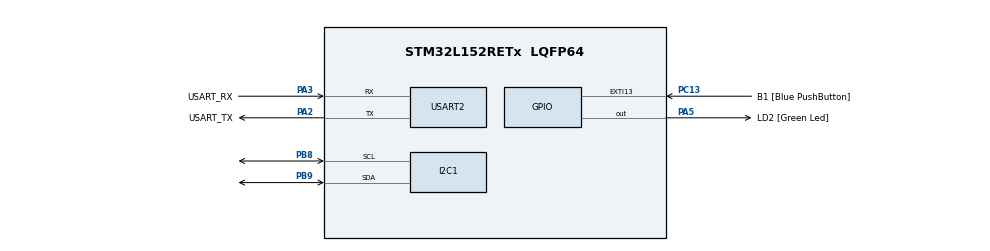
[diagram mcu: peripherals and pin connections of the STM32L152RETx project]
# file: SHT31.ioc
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Mcu.Family=STM32L1
Mcu.Name=STM32L152RETx
Mcu.Package=LQFP64
NVIC.PriorityGroup=NVIC_PRIORITYGROUP_0
PA13.GPIO_Label=TMS
PA13.Mode=Serial_Wire
PA13.Signal=SYS_JTMS-SWDIO
PA14.GPIO_Label=TCK
PA14.Mode=Serial_Wire
PA14.Signal=SYS_JTCK-SWCLK
PA2.GPIO_Label=USART_TX
PA2.Mode=Asynchronous
PA2.Signal=USART2_TX
PA3.GPIO_Label=USART_RX
PA3.Mode=Asynchronous
PA3.Signal=USART2_RX
PA5.GPIO_Label=LD2 [Green Led]
PA5.Signal=GPIO_Output
PB3.GPIO_Label=SWO
PB3.Signal=SYS_JTDO-TRACESWO
PB8.Mode=I2C
PB8.Signal=I2C1_SCL
PB9.Mode=I2C
PB9.Signal=I2C1_SDA
PC13-WKUP2.GPIO_Label=B1 [Blue PushButton]
PC13-WKUP2.Signal=GPXTI13
PC14-OSC32_IN.Mode=LSE-External-Oscillator
PC14-OSC32_IN.Signal=RCC_OSC32_IN
PC15-OSC32_OUT.Mode=LSE-External-Oscillator
PC15-OSC32_OUT.Signal=RCC_OSC32_OUT
PH0-OSC_IN.Mode=HSE-External-Clock-Source
PH0-OSC_IN.Signal=RCC_OSC_IN
PH1-OSC_OUT.Signal=RCC_OSC_OUT
ProjectManager.HeapSize=0x200
ProjectManager.StackSize=0x400
ProjectManager.TargetToolchain=STM32CubeIDE
RCC.48MHZClocksFreq_Value=48000000
RCC.AHBFreq_Value=32000000
RCC.APB1Freq_Value=32000000
RCC.APB1TimFreq_Value=32000000
RCC.APB2Freq_Value=32000000
RCC.APB2TimFreq_Value=32000000
RCC.HCLKFreq_Value=32000000
RCC.HSE_VALUE=8000000
RCC.HSI_VALUE=16000000
RCC.MSI_VALUE=2097000
RCC.PLLDIV=RCC_PLL_DIV3
RCC.PLLMUL=RCC_PLL_MUL6
RCC.RTCClockSelectionVirtual=RCC_RTCCLKSOURCE_LSE
RCC.SYSCLKFreq_VALUE=32000000
RCC.SYSCLKSource=RCC_SYSCLKSOURCE_PLLCLK
RCC.USBOutput=48000000
RCC.VCOOutputFreq_Value=96000000
USART2.VirtualMode=VM_ASYNC
board=NUCLEO-L152RE

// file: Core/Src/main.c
/* USER CODE BEGIN Header */
/**
  ******************************************************************************
  * @file           : main.c
  * @brief          : Main program body
  ******************************************************************************
  * @attention
  *
  * Copyright (c) 2024 STMicroelectronics.
  * All rights reserved.
  *
  * This software is licensed under terms that can be found in the LICENSE file
  * in the root directory of this software component.
  * If no LICENSE file comes with this software, it is provided AS-IS.
  *
  ******************************************************************************
  */
/* USER CODE END Header */
#include "main.h"
#include "i2c.h"
#include "usart.h"
#include "gpio.h"

/* USER CODE BEGIN Includes */
#include "MY_DHT22.h"
/* USER CODE END Includes */

/* USER CODE BEGIN PV */
/* Private variables ---------------------------------------------------------*/

/* USER CODE END PV */

void SystemClock_Config(void);
/* USER CODE BEGIN PFP */
/* Private function prototypes -----------------------------------------------*/

/* USER CODE END PFP */

/* USER CODE BEGIN 0 */
float TempC, Humidity;
char uartData[50];
/* USER CODE END 0 */

int main(void)
{

  /* MCU Configuration--------------------------------------------------------*/

  /* Reset of all peripherals, Initializes the Flash interface and the Systick. */
  HAL_Init();

  /* Configure the system clock */
  SystemClock_Config();

  /* Initialize all configured peripherals */
  MX_GPIO_Init();
  MX_USART2_UART_Init();
  MX_I2C1_Init();
  /* USER CODE BEGIN 2 */
	DHT22_Init(GPIOA, GPIO_PIN_8);
  /* USER CODE END 2 */

  /* Infinite loop */
  while (1)
  {

    /* USER CODE BEGIN 3 */
		if(DHT22_GetTemp_Humidity(&TempC, &Humidity) == 1)
		{
			sprintf(uartData, "\r\nTemp (C) =\t %.1f\r\nHumidity (%%) =\t %.1f%%\r\n", TempC, Humidity);
			HAL_UART_Transmit(&huart2, (uint8_t *)uartData, strlen(uartData), 10);
		}
		else
		{
			sprintf(uartData, "\r\nCRC Error!\r\n");
			HAL_UART_Transmit(&huart2, (uint8_t *)uartData, strlen(uartData), 10);
		}

		HAL_Delay(1000);

  }
  /* USER CODE END 3 */
}

void SystemClock_Config(void)
{
  RCC_OscInitTypeDef RCC_OscInitStruct = {0};
  RCC_ClkInitTypeDef RCC_ClkInitStruct = {0};

  /** Configure the main internal regulator output voltage
  */
  if (HAL_PWREx_ControlVoltageScaling(PWR_REGULATOR_VOLTAGE_SCALE1) != HAL_OK)
  {
    Error_Handler();
  }

  /** Initializes the RCC Oscillators according to the specified parameters
  * in the RCC_OscInitTypeDef structure.
  */
  RCC_OscInitStruct.OscillatorType = RCC_OSCILLATORTYPE_HSI;
  RCC_OscInitStruct.HSIState = RCC_HSI_ON;
  RCC_OscInitStruct.HSICalibrationValue = RCC_HSICALIBRATION_DEFAULT;
  RCC_OscInitStruct.PLL.PLLState = RCC_PLL_ON;
  RCC_OscInitStruct.PLL.PLLSource = RCC_PLLSOURCE_HSI;
  RCC_OscInitStruct.PLL.PLLM = 1;
  RCC_OscInitStruct.PLL.PLLN = 10;
  RCC_OscInitStruct.PLL.PLLP = RCC_PLLP_DIV7;
  RCC_OscInitStruct.PLL.PLLQ = RCC_PLLQ_DIV2;
  RCC_OscInitStruct.PLL.PLLR = RCC_PLLR_DIV2;
  if (HAL_RCC_OscConfig(&RCC_OscInitStruct) != HAL_OK)
  {
    Error_Handler();
  }

  /** Initializes the CPU, AHB and APB buses clocks
  */
  RCC_ClkInitStruct.ClockType = RCC_CLOCKTYPE_HCLK|RCC_CLOCKTYPE_SYSCLK
                              |RCC_CLOCKTYPE_PCLK1|RCC_CLOCKTYPE_PCLK2;
  RCC_ClkInitStruct.SYSCLKSource = RCC_SYSCLKSOURCE_PLLCLK;
  RCC_ClkInitStruct.AHBCLKDivider = RCC_SYSCLK_DIV1;
  RCC_ClkInitStruct.APB1CLKDivider = RCC_HCLK_DIV1;
  RCC_ClkInitStruct.APB2CLKDivider = RCC_HCLK_DIV1;

  if (HAL_RCC_ClockConfig(&RCC_ClkInitStruct, FLASH_LATENCY_4) != HAL_OK)
  {
    Error_Handler();
  }
}

void Error_Handler(void)
{
  while(1)
  {
  }
}
